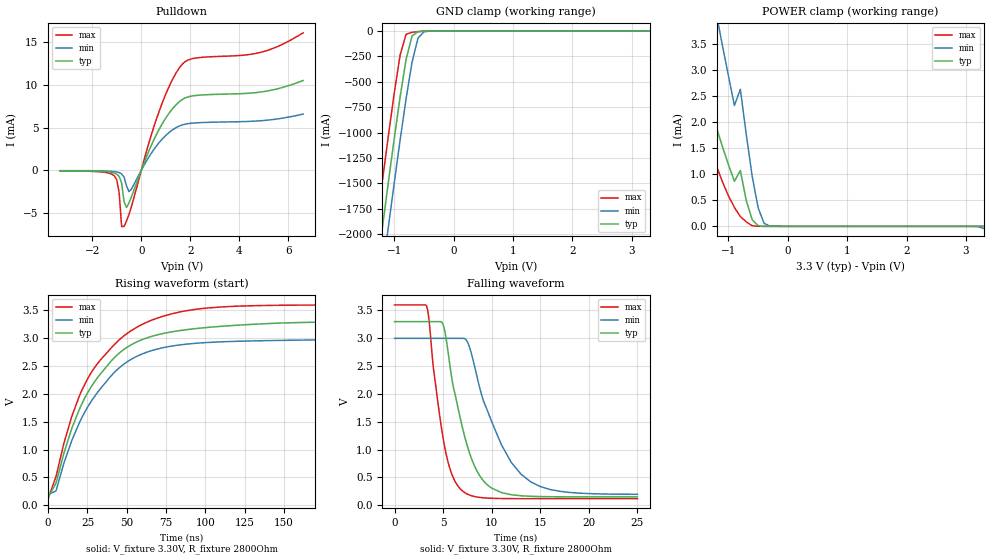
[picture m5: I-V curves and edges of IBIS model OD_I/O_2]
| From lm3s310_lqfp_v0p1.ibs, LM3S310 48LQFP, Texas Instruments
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[Model]   OD_I/O_2
Model_type   I/O_open_drain
Polarity   Inverting
Vinl = 1.26
Vinh = 2.04
Vmeas = 1.65
Rref = 2800
Vref = 3.3
| variable   typ   min   max
C_comp   9.739pF   9.739pF   9.739pF
[Model Spec]
Vinh+   1.91   1.78   2.04
Vinh-   1.90   1.76   2.03
Vinl+   1.40   1.27   1.54
Vinl-   1.39   1.26   1.53
| variable   typ   min   max
[Temperature Range]  25   85   -40
[Voltage Range]   3.3V   3.0V   3.6V
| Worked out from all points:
|   slope of the pulldown table from 0 to 0.495 V, typ, clamps not added: 143 ohm
|   GND clamp passes 1 mA (typ) near -0.48 V on its own axis
|   POWER clamp passes 1 mA (typ) near -0.79 V on its own axis
|   falling waveform, V_fixture 3.30V, R_fixture 2800Ohm: 20-80 % time 2.47ns typ, 3.76ns min, 1.68ns max; typ from 3.3 V to 0.149 V
|   rising waveform, V_fixture 3.30V, R_fixture 2800Ohm: 20-80 % time 34.2ns typ, 33.9ns min, 35.2ns max; typ from 0.149 V to 3.3 V
[Pulldown]
|  Voltage   I(typ)   I(min)   I(max)
-3.3V     -64.15uA   -36.41uA   -91.14uA
-1.1V     -318.3uA   -146.9uA   -641.8uA
-900mV    -721.3uA   -265.2uA   -2.635mA
-800mV    -1.498mA   -417.6uA   -6.598mA
-700mV    -3.678mA   -803.7uA   -6.582mA
-600mV    -4.358mA   -1.83mA    -5.933mA
-500mV    -3.814mA   -2.5mA     -5.165mA
700mV     4.654mA    3.152mA    6.687mA
1.2V      6.961mA    4.59mA     10.23mA
1.7V      8.361mA    5.354mA    12.53mA
4.9V      9.201mA    5.826mA    13.87mA
6.6V      10.54mA    6.604mA    16.13mA
[GND Clamp]
|  Voltage   I(typ)   I(min)   I(max)
-3.3V     -11.72A    -12.12A    -11.3A
-1.4V     -2.845A    -3.285A    -2.387A
-1.3V     -2.39A     -2.831A    -1.93A
-1.2V     -1.938A    -2.38A     -1.478A
-1.1V     -1.494A    -1.934A    -1.036A
-1V       -1.059A    -1.496A    -610.6mA
-900mV    -645mA     -1.069A    -232.9mA
-800mV    -277.1mA   -664.4mA   -31.59mA
-700mV    -48.56mA   -306.6mA   -12.09mA
-600mV    -5.558mA   -70.2mA    -6.272mA
-500mV    -1.167mA   -7.879mA   -2.167mA
3.3V      2.282nA    3.101uA    451.3pA
[POWER Clamp]
|  Voltage   I(typ)   I(min)   I(max)
-3.3V     12.41mA    17.26mA    12.22mA
-1.9V     4.919mA    8.328mA    4.074mA
-1.8V     4.445mA    7.705mA    3.587mA
-1.6V     3.533mA    6.47mA     2.675mA
-1.2V     1.89mA     4.055mA    1.153mA
-1.1V     1.526mA    3.468mA    851.4uA
-900mV    866.3uA    2.324mA    364.9uA
-800mV    1.074mA    2.635mA    188.8uA
-600mV    127.8uA    958.5uA    11.41uA
-500mV    11.24uA    355.9uA    954.7nA
-300mV    9.515nA    3.101uA    1.472nA
3.3V      -104.7pA   -40.34uA   119.2pA
[Ramp]
| variable   typ   min   max
dV/dt_f   1.89/2.47n   1.68/3.76n   2.09/1.68n
dV/dt_r   1.89/34.19n   1.68/33.88n   2.09/35.17n
R_load = 2800Ohm
[Falling Waveform]
V_fixture = 3.30V
V_fixture_min = 3.00V
V_fixture_max = 3.60V
R_fixture = 2800Ohm
|   Time   V(typ)   V(min)   V(max)
0s        3.3V       2.999V     3.6V
3.3ns     3.3V       2.999V     3.583V
4ns       3.3V       2.999V     2.465V
5.2ns     3.106V     2.999V     1.015V
7ns       1.39V      2.999V     255.7mV
7.7ns     949.1mV    2.851V     184.4mV
9.2ns     428.9mV    1.854V     131.9mV
13ns      169.1mV    560.1mV    117.1mV
17ns      150.6mV    249.6mV    116.6mV
25ns      149mV      195.1mV    116.5mV
[Rising Waveform]
V_fixture = 3.30V
V_fixture_min = 3.00V
V_fixture_max = 3.60V
R_fixture = 2800Ohm
|   Time   V(typ)   V(min)   V(max)
0s        148.9mV    194.6mV    116.4mV
5ns       392.6mV    255.5mV    514.6mV
10ns      933.1mV    754.1mV    1.111V
15ns      1.376V     1.159V     1.592V
25ns      2.014V     1.757V     2.264V
43ns      2.675V     2.411V     2.912V
60ns      2.978V     2.72V      3.251V
82ns      3.131V     2.874V     3.461V
110ns     3.215V     2.936V     3.563V
250ns     3.298V     2.994V     3.599V
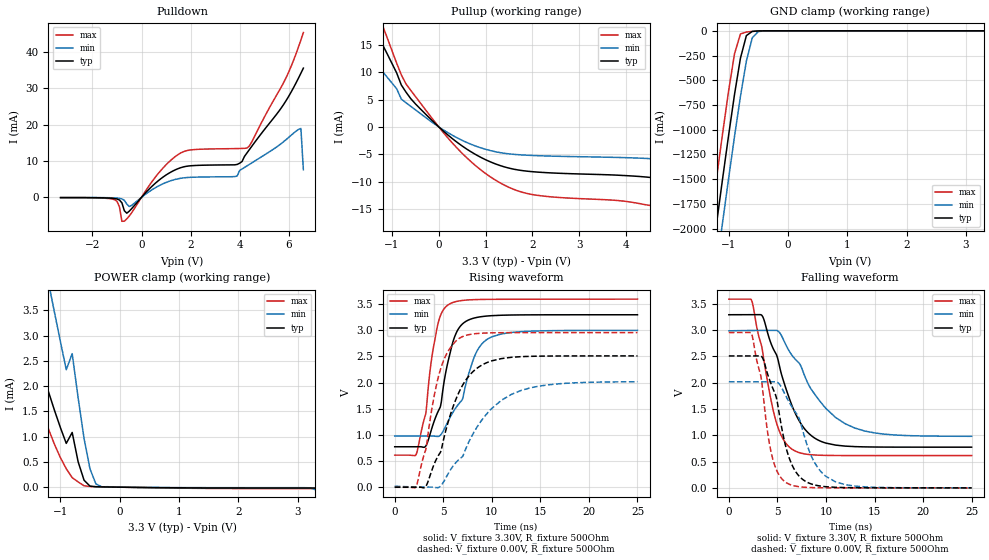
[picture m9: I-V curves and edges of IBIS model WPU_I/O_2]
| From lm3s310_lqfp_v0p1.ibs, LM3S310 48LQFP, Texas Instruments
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[Model]   WPU_I/O_2
Model_type   I/O
Vinl = 1.26
Vinh = 2.04
Vmeas = 1.65
| variable   typ   min   max
C_comp   9.739pF   9.739pF   9.739pF
[Model Spec]
Vinh+   1.91   1.78   2.04
Vinh-   1.90   1.76   2.03
Vinl+   1.40   1.27   1.54
Vinl-   1.39   1.26   1.53
| variable   typ   min   max
[Temperature Range]  25   85   -40
[Voltage Range]   3.3V   3.0V   3.6V
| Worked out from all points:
|   slope of the pulldown table from 0 to 0.495 V, typ, clamps not added: 143 ohm
|   slope of the pullup table from 0 to 0.495 V, typ, clamps not added: 143 ohm
|   GND clamp passes 1 mA (typ) near -0.48 V on its own axis
|   POWER clamp passes 1 mA (typ) near -0.79 V on its own axis
|   falling waveform, V_fixture 3.30V, R_fixture 500Ohm: 20-80 % time 2.98ns typ, 4.47ns min, 2.01ns max; typ from 3.29 V to 0.774 V
|   rising waveform, V_fixture 3.30V, R_fixture 500Ohm: 20-80 % time 1.93ns typ, 2.61ns min, 1.4ns max; typ from 0.774 V to 3.3 V
|   falling waveform, V_fixture 0.00V, R_fixture 500Ohm: 20-80 % time 2.07ns typ, 2.83ns min, 1.51ns max; typ from 2.51 V to 0 V
|   rising waveform, V_fixture 0.00V, R_fixture 500Ohm: 20-80 % time 2.98ns typ, 4.63ns min, 1.94ns max; typ from 0.003 V to 2.51 V
[Pulldown]
|  Voltage   I(typ)   I(min)   I(max)
-3.3V     -63.97uA   -36.29uA   -90.87uA
-1.1V     -317.2uA   -146.3uA   -639.5uA
-800mV    -1.496mA   -416.5uA   -6.587mA
-700mV    -3.674mA   -802.3uA   -6.56mA
-500mV    -3.8mA     -2.497mA   -5.141mA
700mV     4.671mA    3.162mA    6.715mA
1.6V      8.18mA     5.265mA    12.23mA
3.9V      9.066mA    5.872mA    13.44mA
4.3V      12.23mA    8.664mA    13.57mA
5.8V      25.64mA    15.37mA    31.66mA
6.5V      34.2mA     18.98mA    43.35mA
6.6V      35.59mA    7.631mA    45.39mA
[Pullup]
|  Voltage   I(typ)   I(min)   I(max)
-3.3V     48.79mA    30.89mA    64.34mA
-2V       27.61mA    18.17mA    34.74mA
-1.4V     18.31mA    12.15mA    22.87mA
-1.2V     15mA       10.09mA    18.49mA
-700mV    6.347mA    4.415mA    7.843mA
0V        3.344pA    -147.8fA   3.649pA
800mV     -5.101mA   -3.531mA   -7.171mA
1.5V      -7.517mA   -4.914mA   -11.03mA
2.1V      -8.234mA   -5.241mA   -12.47mA
5V        -9.795mA   -6.104mA   -15.25mA
5.8V      -11.66mA   -7.125mA   -18.25mA
6.6V      -15.14mA   -9.034mA   -24.12mA
[GND Clamp]
|  Voltage   I(typ)   I(min)   I(max)
-3.3V     -11.72A    -12.12A    -11.3A
-1.4V     -2.845A    -3.285A    -2.387A
-1.3V     -2.39A     -2.831A    -1.93A
-1.2V     -1.938A    -2.38A     -1.478A
-1.1V     -1.494A    -1.934A    -1.036A
-1V       -1.059A    -1.496A    -610.6mA
-900mV    -645mA     -1.069A    -232.9mA
-800mV    -277.1mA   -664.4mA   -31.6mA
-700mV    -48.56mA   -306.6mA   -12.11mA
-600mV    -5.565mA   -70.2mA    -6.295mA
-500mV    -1.181mA   -7.883mA   -2.192mA
3.3V      2.282nA    6.919uA    -6.848uA
[POWER Clamp]
|  Voltage   I(typ)   I(min)   I(max)
-3.3V     12.41mA    17.26mA    12.22mA
-1.9V     4.919mA    8.328mA    4.074mA
-1.8V     4.445mA    7.705mA    3.587mA
-1.6V     3.533mA    6.47mA     2.675mA
-1.2V     1.89mA     4.055mA    1.153mA
-1.1V     1.526mA    3.468mA    851.4uA
-900mV    866.3uA    2.324mA    364.9uA
-800mV    1.083mA    2.641mA    188.8uA
-600mV    138.2uA    964.3uA    27.06uA
-500mV    20.59uA    361.5uA    14.14uA
-300mV    5.5uA      6.919uA    7.727uA
3.3V      -16.69uA   -49.93uA   -27.55uA
[Ramp]
| variable   typ   min   max
dV/dt_f   1.51/2.98n   1.20/4.47n   1.79/2.01n
dV/dt_r   1.50/2.98n   1.20/4.63n   1.77/1.94n
R_load = 500Ohm
[Falling Waveform]
V_fixture = 3.30V
V_fixture_min = 3.00V
V_fixture_max = 3.60V
R_fixture = 500Ohm
|   Time   V(typ)   V(min)   V(max)
0s        3.294V     2.988V     3.591V
2.3ns     3.295V     2.994V     3.585V
3.4ns     3.283V     2.996V     2.681V
4.8ns     2.569V     2.997V     1.306V
5.6ns     2.051V     2.829V     925.4mV
6.6ns     1.52V      2.499V     724.4mV
8.7ns     965mV      1.82V      627.3mV
12ns      794.2mV    1.218V     614.8mV
16ns      775.8mV    1.022V     614.2mV
25ns      774.3mV    980.9mV    614.1mV
[Rising Waveform]
V_fixture = 3.30V
V_fixture_min = 3.00V
V_fixture_max = 3.60V
R_fixture = 500Ohm
|   Time   V(typ)   V(min)   V(max)
0s        774.3mV    980.1mV    614.1mV
2.2ns     774.3mV    980mV      622.5mV
3.2ns     787mV      979.9mV    1.407V
3.7ns     1.052V     980.1mV    2.318V
4.4ns     1.421V     971mV      3.079V
5.5ns     2.409V     1.264V     3.484V
6.9ns     3.106V     1.658V     3.567V
8.3ns     3.238V     2.536V     3.585V
9.9ns     3.277V     2.866V     3.59V
25ns      3.296V     2.998V     3.594V
[Falling Waveform]
V_fixture = 0.00V
V_fixture_min = 0.00V
V_fixture_max = 0.00V
R_fixture = 500Ohm
|   Time   V(typ)   V(min)   V(max)
0s        2.51V      2.018V     2.956V
2.3ns     2.51V      2.018V     2.949V
3.4ns     2.496V     2.018V     2.006V
4.4ns     1.953V     2.018V     640.4mV
4.9ns     1.714V     2.015V     343.1mV
5.9ns     759.2mV    1.738V     101.1mV
7.6ns     161.2mV    1.097V     14.72mV
9ns       48.57mV    430.3mV    3.464mV
11ns      10.29mV    113.3mV    565.4uV
25ns      33.59uV    149.8uV    22.64uV
[Rising Waveform]
V_fixture = 0.00V
V_fixture_min = 0.00V
V_fixture_max = 0.00V
R_fixture = 500Ohm
|   Time   V(typ)   V(min)   V(max)
0s        2.842mV    22.04mV    193.5uV
2.2ns     619.5uV    6.783mV    11mV
3.2ns     15.34mV    4.118mV    717mV
4ns       413.4mV    1.736mV    1.68V
4.7ns     664.9mV    17.25mV    2.244V
6.7ns     1.847V     544.4mV    2.851V
9.2ns     2.357V     1.34V      2.946V
12ns      2.483V     1.773V     2.954V
16ns      2.507V     1.961V     2.955V
25ns      2.51V      2.016V     2.955V
